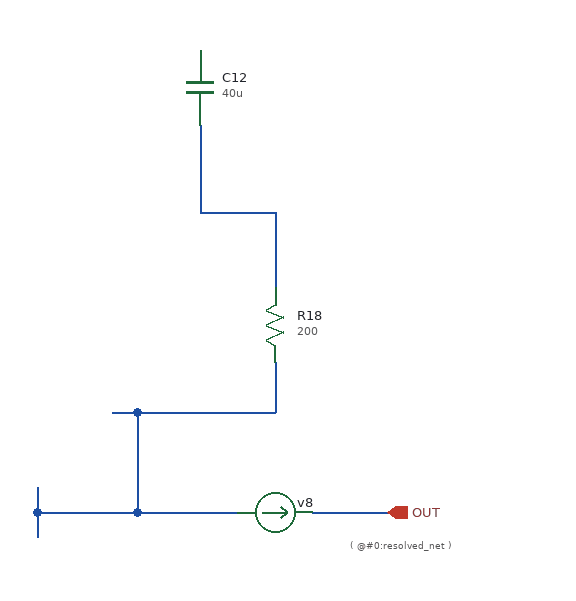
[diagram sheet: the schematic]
v {xschem version=3.4.8RC file_version=1.3}
G {}
K {}
V {}
S {}
F {}
E {}
T {( @#0:resolved_net )} -300 155 0 1 0.2 0.2 {name=p5 layer=15}
N -550 140 -550 160 {lab=#net1}
N -550 120 -550 140 {lab=#net1}
N -330 140 -270 140 {lab=OUT}
N -550 140 -470 140 {lab=#net1}
N -470 140 -390 140 {lab=#net1}
N -420 -170 -420 -100 {lab=#net2}
N -360 -100 -360 -40 {lab=#net2}
N -470 60 -360 60 {lab=#net1}
N -420 -100 -360 -100 {lab=#net2}
N -490 60 -470 60 {lab=#net1}
N -470 60 -470 140 {lab=#net1}
N -360 20 -360 60 {lab=#net1}
C {devices/capa} -420 -200 0 0 {name=C12 m=1 value="40u"}
C {devices/res} -360 -10 0 1 {name=R18 m=1 value=200}
C {devices/ammeter} -360 140 3 0 {name=v8}
C {devices/opin} -270 140 0 0 {name=p5 lab=OUT}
